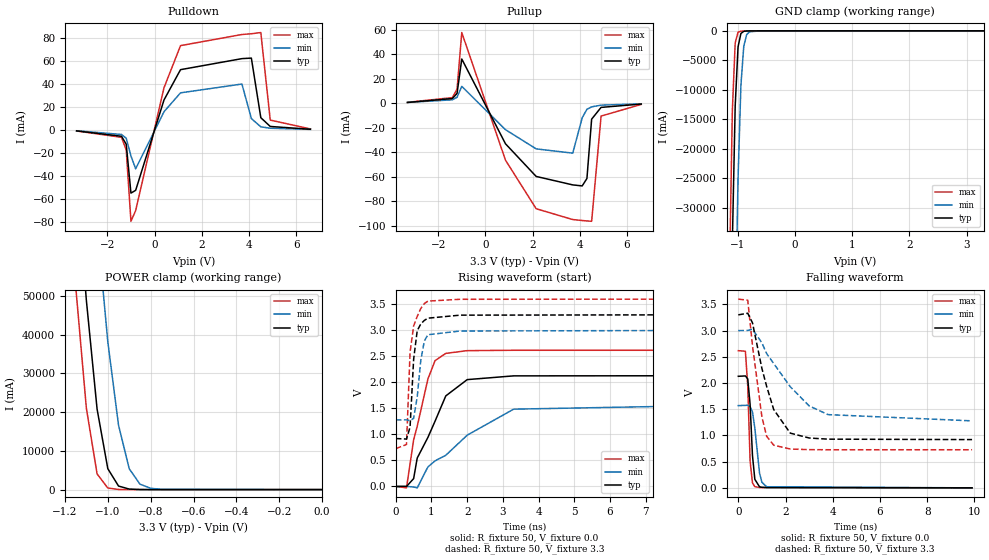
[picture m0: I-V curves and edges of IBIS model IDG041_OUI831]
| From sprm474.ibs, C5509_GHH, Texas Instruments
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| Pin_model   IDG041_OUI831
[Model]   IDG041_OUI831
 Model_type   I/O
 Polarity   Non-Inverting
 Enable   Active-Low
 Vinl  =  1.08
 Vinh  =  2.10
 Vmeas =  1.125
|Variable   typ   min   max
 C_comp   2.349pF   2.328pF   2.418pF
[Temperature Range]   25   125   -40
[Voltage Range]   3.3   3.0   3.6
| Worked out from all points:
|   slope of the pulldown table from 0 to 0.495 V, typ, clamps not added: 16 ohm
|   slope of the pullup table from 0 to 0.495 V, typ, clamps not added: 23.8 ohm
|   GND clamp passes 1 mA (typ) near -0.59 V on its own axis
|   POWER clamp passes 1 mA (typ) near -0.70 V on its own axis
|   rising waveform, R_fixture 50, V_fixture 0.0: 20-80 % time 803ps typ, 1.58ns min, 481ps max; typ from 0 V to 2.13 V
|   rising waveform, R_fixture 50, V_fixture 3.3: 20-80 % time 150ps typ, 185ps min, 160ps max; typ from 0.921 V to 3.3 V
|   falling waveform, R_fixture 50, V_fixture 0.0: 20-80 % time 165ps typ, 228ps min, 121ps max; typ from 2.13 V to 0 V
|   falling waveform, R_fixture 50, V_fixture 3.3: 20-80 % time 870ps typ, 1.74ns min, 490ps max; typ from 3.3 V to 0.921 V
[GND Clamp]
|Voltage   I(typ)   I(min)   I(max)
-3.3V     -2.131kA   -2.172kA   -2.112kA
-1.15V    -69.25A    -121A      -41.3A
-1.1V     -36.04A    -83.7A     -13.64A
-1.05V    -12.77A    -50.83A    -2.067A
-1V       -2.726A    -25.08A    -235.7mA
-950mV    -452.7mA   -9.272A    -58.81mA
-900mV    -87.44mA   -2.634A    -35.32mA
-850mV    -28.97mA   -661.7mA   -25.37mA
-800mV    -15.75mA   -165.5mA   -17.41mA
-600mV    -1.159mA   -2.524mA   -779.4uA
3.3V      218.1pA    2.598nA    184.3pA
[POWER Clamp]
|Voltage   I(typ)   I(min)   I(max)
-3.3V     2.152kA    2.199kA    2.128kA
-1.15V    84.65A     142.8A     52.53A
-1.1V     48.8A      103.8A     20.98A
-1.05V    20.76A     68.2A      4.051A
-1V       5.397A     38.14A     408.9mA
-950mV    921mA      16.63A     39.31mA
-900mV    138.5mA    5.377A     6.91mA
-850mV    22mA       1.408A     3.323mA
-800mV    4.66mA     339.8mA    2.313mA
-750mV    1.713mA    80.91mA    1.624mA
0V        0A         0A         0A
[Pulldown]
|Voltage   I(typ)   I(min)   I(max)
-3.3V     -700uA     -600uA     -800uA
-1.4V     -5.37mA    -3.81mA    -6.26mA
-1.2V     -12.25mA   -7.11mA    -17.31mA
-1V       -54.58mA   -22.44mA   -78.99mA
-800mV    -52.16mA   -33.54mA   -69.68mA
400mV     26.07mA    15.89mA    36.64mA
1.1V      52.31mA    32.25mA    73.11mA
3.7V      61.86mA    39.87mA    82.75mA
4.1V      62.32mA    9.97mA     83.41mA
4.5V      10.72mA    2.83mA     84.43mA
4.9V      3.13mA     1.59mA     8.65mA
6.6V      700uA      600uA      1mA
[Pullup]
|Voltage   I(typ)   I(min)   I(max)
-3.3V     500uA      500uA      600uA
-1.4V     3.68mA     2.67mA     4.45mA
-1.2V     7.89mA     4.73mA     11.41mA
-1V       35.94mA    13.64mA    57.52mA
850mV     -33.18mA   -21.68mA   -46.54mA
2.15V     -59.85mA   -37.37mA   -86.19mA
3.7V      -66.75mA   -40.84mA   -95.02mA
4.1V      -67.58mA   -12.01mA   -95.82mA
4.3V      -61.52mA   -5.05mA    -96.15mA
4.5V      -13.12mA   -3.07mA    -96.45mA
4.9V      -3.53mA    -1.69mA    -10.6mA
6.6V      -800uA     -600uA     -1.1mA
[Ramp]
|Variable   typ   min   max
 dV/dt_r   1.29V/0.810ns   0.95V/1.590ns   1.59V/0.490ns
 dV/dt_f   1.43V/0.870ns   1.03V/1.740ns   1.72V/0.490ns
 R_load =  50
[Rising Waveform]
 R_fixture =   50
 V_fixture =   0.0
 V_fixture_min =  0.0
 V_fixture_max =  0.0
|Time   V(typ)   V(min)   V(max)
0s        19.75nV    2.537uV    10.29nV
300ps     -534.5uV   1.303mV    -26.94mV
500ps     150.3mV    -11.46mV   896.2mV
600ps     544.8mV    -27.42mV   1.155V
900ps     943.1mV    375.1mV    2.066V
1.1ns     1.255V     491.4mV    2.419V
1.4ns     1.74V      598.7mV    2.557V
2ns       2.053V     985.1mV    2.61V
3.3ns     2.125V     1.485V     2.617V
9.9ns     2.128V     1.569V     2.617V
[Rising Waveform]
 R_fixture =   50
 V_fixture =   3.3
 V_fixture_min =  3.0
 V_fixture_max =  3.6
|Time   V(typ)   V(min)   V(max)
0s        920.7mV    1.278V     727mV
300ps     910.9mV    1.279V     805.9mV
400ps     1.141V     1.262V     2.579V
500ps     2.444V     1.311V     3.085V
600ps     2.993V     1.716V     3.267V
700ps     3.123V     2.423V     3.42V
800ps     3.191V     2.796V     3.515V
900ps     3.234V     2.916V     3.562V
1.8ns     3.292V     2.987V     3.597V
9.9ns     3.3V       3V         3.6V
[Falling Waveform]
 R_fixture =   50
 V_fixture =   0.0
 V_fixture_min =  0.0
 V_fixture_max =  0.0
|Time   V(typ)   V(min)   V(max)
0s        2.128V     1.569V     2.617V
300ps     2.135V     1.573V     2.606V
400ps     2.079V     1.577V     1.946V
500ps     1.589V     1.55V      506.9mV
600ps     616.9mV    1.448V     95.51mV
700ps     162.5mV    1.14V      21.83mV
900ps     19.79mV    279.9mV    7.578mV
1ns       11.03mV    106.7mV    6.057mV
1.2ns     6.473mV    21.04mV    4.118mV
9.9ns     -41.66nV   2.177uV    20.69nV
[Falling Waveform]
 R_fixture =   50
 V_fixture =   3.3
 V_fixture_min =  3.0
 V_fixture_max =  3.6
|Time   V(typ)   V(min)   V(max)
0s        3.3V       3V         3.6V
400ps     3.331V     3.003V     3.58V
600ps     3.148V     3.027V     2.714V
1ns       2.277V     2.765V     1.352V
1.2ns     1.937V     2.561V     984.1mV
1.5ns     1.494V     2.371V     813.4mV
2.2ns     1.044V     1.929V     741mV
3ns       951mV      1.564V     728.9mV
3.8ns     929mV      1.397V     727mV
9.9ns     920.7mV    1.278V     727mV
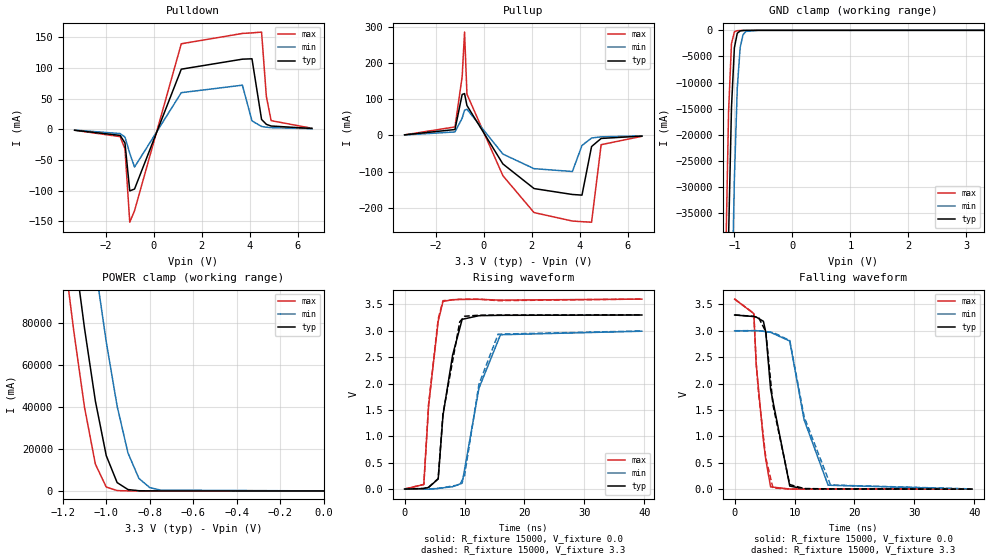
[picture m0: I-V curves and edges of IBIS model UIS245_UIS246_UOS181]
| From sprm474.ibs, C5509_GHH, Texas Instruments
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| Pin_model   UIS245_UIS246_UOS181
[Model]   UIS245_UIS246_UOS181
 Model_type   I/O
 Polarity   Non-Inverting
 Enable   Active-Low
 Vinl  =  1.08
 Vinh  =  2.1
 Vmeas =  1.5
|Variable   typ   min   max
 C_comp   4.097pF   3.592pF   4.335pF
[Temperature Range]   25   125   -40
[Voltage Range]   3.3   3   3.6
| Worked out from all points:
|   slope of the pulldown table from 0 to 0.495 V, typ, clamps not added: 8.77 ohm
|   slope of the pullup table from 0 to 0.495 V, typ, clamps not added: 9.51 ohm
|   GND clamp passes 1 mA (typ) near -0.59 V on its own axis
|   POWER clamp passes 1 mA (typ) near -0.63 V on its own axis
|   rising waveform, R_fixture 15000, V_fixture 0.0: 20-80 % time 2.33ns typ, 3.36ns min, 1.64ns max; typ from 0 V to 3.3 V
|   rising waveform, R_fixture 15000, V_fixture 3.3: 20-80 % time 2.23ns typ, 3.14ns min, 1.6ns max; typ from 0.002 V to 3.3 V
|   falling waveform, R_fixture 15000, V_fixture 0.0: 20-80 % time 2.41ns typ, 3.76ns min, 1.64ns max; typ from 3.3 V to 0 V
|   falling waveform, R_fixture 15000, V_fixture 3.3: 20-80 % time 2.49ns typ, 3.97ns min, 1.67ns max; typ from 3.3 V to 0.002 V
[GND Clamp]
|Voltage   I(typ)   I(min)   I(max)
-3.3V     -2.137kA   -2.18kA    -2.117kA
-1.15V    -73.58A    -127.2A    -44.44A
-1.1V     -39.55A    -89.33A    -15.57A
-1.05V    -14.82A    -55.61A    -2.53A
-1V       -3.341A    -28.53A    -286.1mA
-950mV    -561.3mA   -11.06A    -65.77mA
-900mV    -105.2mA   -3.251A    -37.84mA
-850mV    -32.81mA   -825.7mA   -26.85mA
-800mV    -17.15mA   -205.8mA   -18.26mA
-600mV    -1.216mA   -2.851mA   -786.4uA
3.3V      261.1pA    2.159nA    229.2pA
[POWER Clamp]
|Voltage   I(typ)   I(min)   I(max)
-3.3V     2.192kA    2.252kA    2.16kA
-1.2V     159A       230.6A     118A
-1.15V    116.9A     187.7A     76.66A
-1.1V     77.49A     146.2A     39.82A
-1.05V    42.77A     106.9A     12.74A
-1V       16.79A     71A        1.832A
-950mV    3.959A     40.37A     175mA
-900mV    648.9mA    18.03A     22.41mA
-850mV    99.14mA    5.97A      7.754mA
-800mV    17.49mA    1.583A     4.952mA
-750mV    4.802mA    383.9mA    3.37mA
0V        0A         0A         0A
[Pulldown]
|Voltage   I(typ)   I(min)   I(max)
-3.3V     -1.5mA     -1.3mA     -1.6mA
-1.4V     -9.93mA    -6.9mA     -11.91mA
-1.2V     -22.27mA   -12.69mA   -32.18mA
-1V       -100.5mA   -39.12mA   -151.6mA
-800mV    -97.43mA   -61.62mA   -132.8mA
1.15V     98.15mA    59.81mA    139.6mA
3.7V      114.5mA    72.02mA    156.5mA
4.1V      115.1mA    13.78mA    157.4mA
4.5V      16.1mA     4.63mA     158.7mA
4.7V      8.15mA     3.42mA     53.59mA
4.9V      5.37mA     2.71mA     14.16mA
6.6V      1.4mA      1mA        1.7mA
[Pullup]
|Voltage   I(typ)   I(min)   I(max)
-3.3V     1.4mA      1.1mA      1.4mA
-1.2V     16.1mA     9.4mA      23.25mA
-900mV    112.6mA    47.49mA    161.3mA
-800mV    115.2mA    69.14mA    284.7mA
-700mV    82.34mA    72.02mA    113.3mA
800mV     -78.84mA   -51.61mA   -111.3mA
2.1V      -146.7mA   -91.84mA   -212.9mA
3.7V      -163mA     -99.67mA   -236.2mA
4.1V      -164.8mA   -27.93mA   -238mA
4.5V      -30.83mA   -7.37mA    -239.4mA
4.9V      -8.51mA    -4.08mA    -25.72mA
6.6V      -2mA       -1.4mA     -2.6mA
[Ramp]
|Variable   typ   min   max
 dV/dt_r   1.96V/2.320ns   1.81V/3.360ns   2.15V/1.640ns
 dV/dt_f   1.95V/2.480ns   1.81V/4.000ns   2.13V/1.640ns
 R_load =  15000
[Rising Waveform]
 R_fixture =   15000
 V_fixture =   0.0
 V_fixture_min =  0.0
 V_fixture_max =  0.0
|Time   V(typ)   V(min)   V(max)
0s        -5.278nV   -2.079uV   848.3pV
3.2ns     9.849mV    -726.7uV   86.86mV
4ns       32.59mV    -1.66mV    1.585V
5.6ns     192.1mV    11.53mV    3.18V
6.4ns     1.395V     24.05mV    3.555V
8ns       2.535V     44.86mV    3.588V
9.6ns     3.216V     111.9mV    3.593V
12.4ns    3.285V     1.911V     3.595V
16ns      3.292V     2.924V     3.58V
39.6ns    3.298V     2.991V     3.599V
[Rising Waveform]
 R_fixture =   15000
 V_fixture =   3.3
 V_fixture_min =  3
 V_fixture_max =  3.6
|Time   V(typ)   V(min)   V(max)
0s        1.57mV     2.39mV     1.188mV
3.2ns     11.53mV    1.621mV    88.64mV
4ns       34.39mV    768.1uV    1.609V
5.6ns     198.2mV    14.19mV    3.221V
6.4ns     1.428V     26.81mV    3.569V
9.2ns     3.169V     82.29mV    3.596V
10ns      3.274V     254.4mV    3.597V
12.4ns    3.294V     1.985V     3.598V
15.6ns    3.297V     2.935V     3.57V
39.6ns    3.3V       2.996V     3.6V
[Falling Waveform]
 R_fixture =   15000
 V_fixture =   0.0
 V_fixture_min =  0.0
 V_fixture_max =  0.0
|Time   V(typ)   V(min)   V(max)
0s        3.298V     2.997V     3.599V
3.2ns     3.269V     3V         3.324V
3.6ns     3.259V     3V         2.363V
4.8ns     3.179V     2.99V      921.7mV
5.2ns     2.973V     2.983V     558.8mV
6ns       1.894V     2.97V      44.38mV
9.2ns     58.76mV    2.805V     2.006mV
11.6ns    5.486mV    1.312V     800.1uV
15.6ns    1.368mV    74.94mV    6.313mV
39.6ns    34.48nV    559.4uV    79.99pV
[Falling Waveform]
 R_fixture =   15000
 V_fixture =   3.3
 V_fixture_min =  3
 V_fixture_max =  3.6
|Time   V(typ)   V(min)   V(max)
0s        3.3V       3V         3.6V
3.2ns     3.272V     3.003V     3.33V
3.6ns     3.262V     3.003V     2.381V
4ns       3.25V      3.001V     1.798V
5.2ns     2.984V     2.986V     593mV
6.4ns     1.596V     2.968V     20.03mV
9.2ns     86.34mV    2.816V     4.707mV
11.6ns    12.05mV    1.371V     2.805mV
16ns      4.871mV    78.77mV    4.258mV
39.6ns    1.57mV     4.539mV    1.188mV
